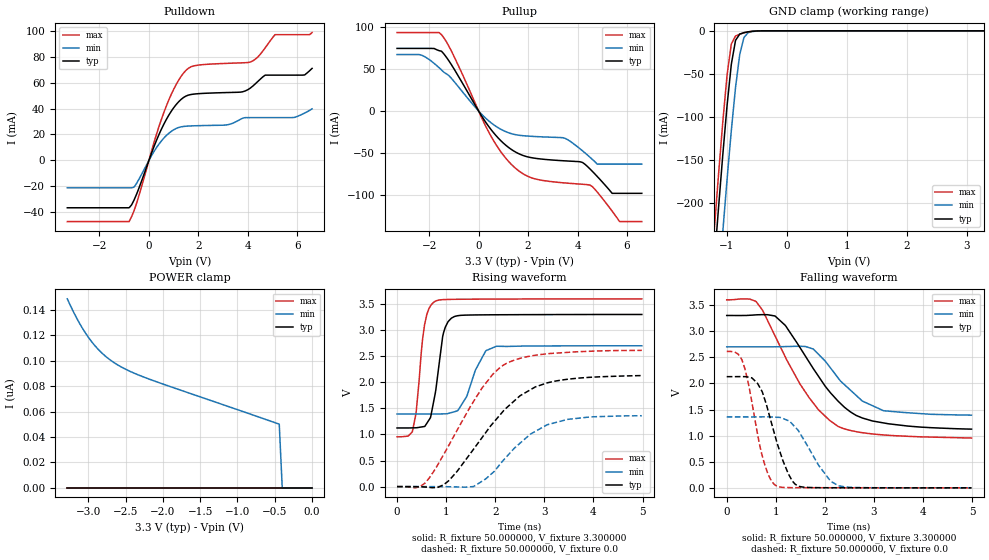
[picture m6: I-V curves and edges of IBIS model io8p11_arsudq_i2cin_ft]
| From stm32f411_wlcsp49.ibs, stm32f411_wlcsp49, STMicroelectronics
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|   Model io8p11_arsudq_i2cin_ft
[Model]  io8p11_arsudq_i2cin_ft
Model_type I/O
Polarity   Non-Inverting
Enable   Active-Low
Vinl =   0.990000V
Vinh =   2.310000V
Vmeas =  1.650000V
Cref =   30.000000pF
Rref =   100.000000M
Vref =   0.0V
C_comp   2.280000pF   2.217100pF   2.355700pF
[Temperature Range]   25.000000   0.125000k   -40.000000
[Pullup Reference]   3.300000V   2.700000V   3.600000V
[Pulldown Reference]   0.0V   0.0V   0.0V
[POWER Clamp Reference]   3.300000V   2.700000V   3.600000V
[GND Clamp Reference]   0.0V   0.0V   0.0V
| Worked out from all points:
|   slope of the pulldown table from 0 to 0.495 V, typ, clamps not added: 20.9 ohm
|   slope of the pullup table from 0 to 0.495 V, typ, clamps not added: 22.6 ohm
|   GND clamp passes 1 mA (typ) near -0.62 V on its own axis
|   rising waveform, R_fixture 50.000000, V_fixture 3.300000: 20-80 % time 197ps typ, 343ps min, 161ps max; typ from 1.12 V to 3.3 V
|   rising waveform, R_fixture 50.000000, V_fixture 0.0: 20-80 % time 1.13ns typ, 914ps min, 1ns max; typ from 0 V to 2.13 V
|   falling waveform, R_fixture 50.000000, V_fixture 3.300000: 20-80 % time 1.01ns typ, 786ps min, 980ps max; typ from 3.3 V to 1.12 V
|   falling waveform, R_fixture 50.000000, V_fixture 0.0: 20-80 % time 415ps typ, 536ps min, 332ps max; typ from 2.13 V to 0 V
[Pulldown]
|Voltage   I(typ)   I(min)   I(max)
-3.3V     -36.46mA   -21.09mA   -47.09mA
-800mV    -36.46mA   -21.09mA   -47.09mA
-600mV    -30.5mA    -20.54mA   -38.69mA
700mV     31.4mA     19.11mA    41.71mA
1.2V      45.15mA    25.37mA    61.75mA
1.6V      50.35mA    26.5mA     71.06mA
3.1V      52.28mA    27.26mA    74.76mA
4.1V      55.7mA     33mA       75.81mA
4.7V      65.72mA    33mA       86.7mA
5.1V      65.72mA    33mA       96.91mA
6.3V      65.88mA    36.51mA    96.91mA
6.6V      70.94mA    39.72mA    98.51mA
[Pullup]
|Voltage   I(typ)   I(min)   I(max)
-3.3V     74.74mA    67.41mA    93.65mA
-2.3V     74.74mA    66.57mA    93.65mA
-1.5V     71.37mA    49mA       91.08mA
500mV     -22.07mA   -14mA      -30.03mA
1.6V      -50.64mA   -28.81mA   -70.96mA
3.5V      -59.53mA   -32.65mA   -85.92mA
4.2V      -61.43mA   -47.49mA   -87.46mA
4.5V      -69.07mA   -55.12mA   -88.38mA
4.8V      -78.23mA   -63.4mA    -96.83mA
5.4V      -98.3mA    -63.4mA    -119.6mA
5.7V      -98.3mA    -63.4mA    -132mA
6.6V      -98.3mA    -63.4mA    -132mA
[GND_clamp]
|Voltage   I(typ)   I(min)   I(max)
-3.3V     -2.317A    -2.396A    -2.289A
-1.2V     -265.5mA   -356.1mA   -227.2mA
-1.13V    -202.6mA   -292.9mA   -164.1mA
-1.06V    -142.2mA   -231.2mA   -104.1mA
-990mV    -85.98mA   -171.6mA   -50.72mA
-920mV    -38.8mA    -115.5mA   -15.28mA
-850mV    -11.08mA   -65.6mA    -6.001mA
-780mV    -3.782mA   -27.42mA   -3.876mA
-710mV    -2.086mA   -7.69mA    -2.381mA
-640mV    -1.147mA   -2.118mA   -1.22mA
-570mV    -523.9uA   -798.4uA   -476.8uA
3.28V     0A         0A         0A
[POWER_clamp]
|Voltage   I(typ)   I(min)   I(max)
-3.28V    0A         148.5nA    0A
-3.2V     0A         138.6nA    0A
-3.12V    0A         129.7nA    0A
-3.04V    0A         122nA      0A
-2.96V    0A         115.3nA    0A
-2.8V     0A         105.1nA    0A
-2.6V     0A         96.44nA    0A
-2.4V     0A         90.52nA    0A
-2.16V    0A         84.97nA    0A
-440mV    0A         50.04nA    0A
-400mV    0A         0A         0A
0V        0A         0A         0A
[Ramp]
| variable   typ   min   max
dV/dt_r  1.26126/1.11621n   0.80562/0.90469n   1.56066/0.99981n
dV/dt_f  1.27692/0.99459n   0.77130/0.76528n   1.56982/0.97122n
R_load = 50.000000
[Rising Waveform]
R_fixture= 50.000000
V_fixture= 3.300000
V_fixture_min= 2.700000
V_fixture_max= 3.600000
|time   V(typ)   V(min)   V(max)
0s        1.124V     1.392V     954.4mV
310.3ps   1.126V     1.392V     1.049V
390.4ps   1.128V     1.392V     1.436V
560.6ps   1.153V     1.392V     3.099V
780.8ps   1.8V       1.391V     3.554V
951ps     2.961V     1.395V     3.585V
1.171ns   3.262V     1.436V     3.59V
1.802ns   3.293V     2.594V     3.594V
2.022ns   3.294V     2.69V      3.595V
4.985ns   3.3V       2.7V       3.599V
[Rising Waveform]
R_fixture= 50.000000
V_fixture= 0.0
V_fixture_min= 0.0
V_fixture_max= 0.0
|time   V(typ)   V(min)   V(max)
0s        345.4uV    196.8uV    641.9uV
470.5ps   -3.051mV   137.9uV    396.5uV
660.7ps   -15.09mV   184.2uV    170.3mV
951ps     36.13mV    -1.055mV   617.8mV
1.562ns   720.9mV    2.76mV     1.636V
1.952ns   1.214V     268.6mV    2.155V
2.202ns   1.487V     543.5mV    2.349V
2.713ns   1.855V     1.003V     2.502V
3.063ns   1.99V      1.187V     2.547V
4.985ns   2.129V     1.359V     2.612V
[Falling Waveform]
R_fixture= 50.000000
V_fixture= 3.300000
V_fixture_min= 2.700000
V_fixture_max= 3.600000
|time   V(typ)   V(min)   V(max)
0s        3.3V       2.7V       3.599V
590.6ps   3.311V     2.7V       3.571V
730.7ps   3.316V     2.7V       3.399V
991ps     3.284V     2.701V     2.895V
1.201ns   3.099V     2.705V     2.49V
1.762ns   2.285V     2.658V     1.625V
2.272ns   1.656V     2.1V       1.174V
2.763ns   1.337V     1.661V     1.056V
3.193ns   1.243V     1.477V     1.013V
4.985ns   1.124V     1.392V     954.4mV
[Falling Waveform]
R_fixture= 50.000000
V_fixture= 0.0
V_fixture_min= 0.0
V_fixture_max= 0.0
|time   V(typ)   V(min)   V(max)
0s        2.129V     1.359V     2.612V
310.3ps   2.129V     1.358V     2.449V
450.5ps   2.118V     1.358V     1.955V
630.6ps   1.995V     1.358V     1.013V
830.8ps   1.516V     1.36V      286.8mV
1.011ns   906.2mV    1.352V     39.04mV
1.391ns   71.92mV    1.165V     3.466mV
1.872ns   3.6mV      431.9mV    2.332mV
2.272ns   2.019mV    42.33mV    1.989mV
4.985ns   345.4uV    196.8uV    641.9uV
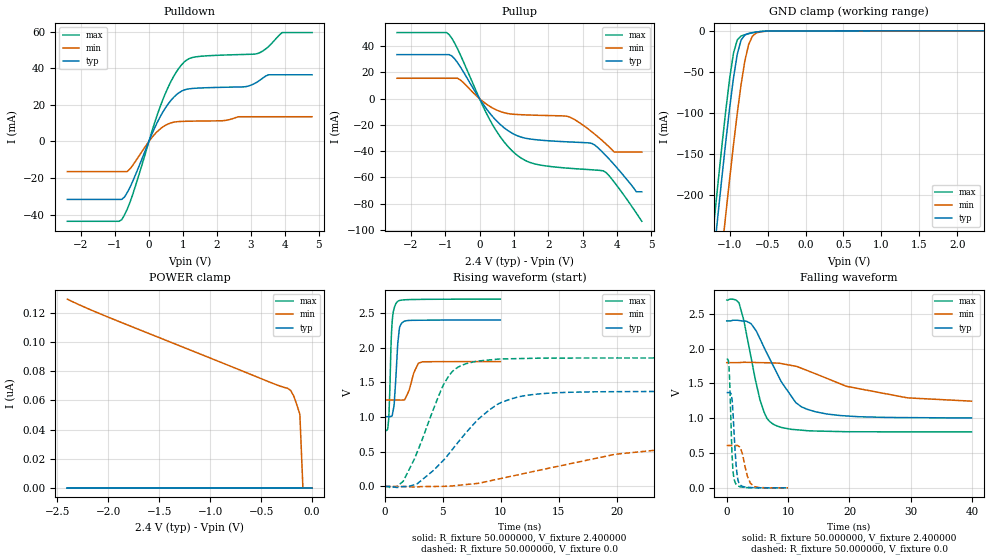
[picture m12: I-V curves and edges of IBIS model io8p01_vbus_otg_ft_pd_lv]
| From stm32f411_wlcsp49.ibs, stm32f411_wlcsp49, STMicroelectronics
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|   Model io8p01_vbus_otg_ft_pd_lv
[Model]  io8p01_vbus_otg_ft_pd_lv
Model_type I/O
Polarity   Non-Inverting
Enable   Active-Low
Vinl =   0.720000V
Vinh =   1.680000V
Vmeas =  1.200000V
Cref =   50.000000pF
Rref =   100.000000M
Vref =   0.0V
C_comp   3.193600pF   3.100000pF   3.332100pF
[Temperature Range]   25.000000   0.125000k   -40.000000
[Pullup Reference]   2.400000V   1.800000V   2.700000V
[Pulldown Reference]   0.0V   0.0V   0.0V
[POWER Clamp Reference]   2.400000V   1.800000V   2.700000V
[GND Clamp Reference]   0.0V   0.0V   0.0V
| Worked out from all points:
|   slope of the pulldown table from 0 to 0.36 V, typ, clamps not added: 25 ohm
|   slope of the pullup table from 0 to 0.36 V, typ, clamps not added: 27.7 ohm
|   GND clamp passes 1 mA (typ) near -0.61 V on its own axis
|   rising waveform, R_fixture 50.000000, V_fixture 2.400000: 20-80 % time 310ps typ, 630ps min, 224ps max; typ from 1 V to 2.4 V
|   rising waveform, R_fixture 50.000000, V_fixture 0.0: 20-80 % time 4.51ns typ, 11ns min, 2.64ns max; typ from 0 V to 1.37 V
|   falling waveform, R_fixture 50.000000, V_fixture 2.400000: 20-80 % time 5.25ns typ, 12.6ns min, 2.75ns max; typ from 2.4 V to 1 V
|   falling waveform, R_fixture 50.000000, V_fixture 0.0: 20-80 % time 574ps typ, 1.04ns min, 434ps max; typ from 1.37 V to 0 V
[Pulldown]
|Voltage   I(typ)   I(min)   I(max)
-2.4V     -31.69mA   -16.5mA    -43.66mA
-800mV    -31.69mA   -16.5mA    -42.82mA
-480mV    -21.96mA   -13.17mA   -29.19mA
80mV      3.63mA     1.966mA    5.014mA
480mV     18.15mA    8.738mA    26.02mA
800mV     25.38mA    10.72mA    37.77mA
1.12V     28.53mA    11.02mA    44.6mA
2.8V      29.84mA    13.49mA    47.53mA
3.2V      32.65mA    13.49mA    48.04mA
3.52V     36.42mA    13.49mA    51.83mA
3.92V     36.42mA    13.49mA    59.49mA
4.8V      36.42mA    13.49mA    59.49mA
[Pullup]
|Voltage   I(typ)   I(min)   I(max)
-2.4V     33.57mA    15.56mA    50.37mA
-960mV    33.57mA    15.56mA    50.37mA
-560mV    24.29mA    14.3mA     33.54mA
320mV     -11.75mA   -6.207mA   -17.08mA
960mV     -26.47mA   -11.82mA   -40.02mA
1.52V     -30.88mA   -12.51mA   -49.05mA
2.56V     -32.88mA   -13.49mA   -52.9mA
3.28V     -34.19mA   -25.52mA   -54.18mA
3.6V      -41.31mA   -32.61mA   -54.99mA
3.92V     -50.33mA   -40.7mA    -63.62mA
4.56V     -70.9mA    -40.7mA    -87.08mA
4.72V     -70.9mA    -40.7mA    -93.4mA
[GND_clamp]
|Voltage   I(typ)   I(min)   I(max)
-2.4V     -1.424A    -1.508A    -1.393A
-1.25V    -311.3mA   -401.9mA   -273.4mA
-1.2V     -265.5mA   -356.1mA   -227.3mA
-1.15V    -220.5mA   -310.9mA   -182mA
-1.1V     -176.4mA   -266.2mA   -138mA
-1.05V    -133.9mA   -222.5mA   -96.06mA
-950mV    -57.51mA   -139mA     -27.36mA
-900mV    -28.55mA   -100.5mA   -11.04mA
-850mV    -11.34mA   -65.68mA   -6.337mA
-750mV    -3.08mA    -16.7mA    -3.439mA
-600mV    -875.9uA   -1.303mA   -865.8uA
2.35V     58.09uA    37.92uA    67.25uA
[POWER_clamp]
|Voltage   I(typ)   I(min)   I(max)
-2.4V     0A         129.4nA    0A
-1.98V    0A         116.5nA    0A
-390mV    0A         71.78nA    0A
-240mV    0A         68.22nA    0A
-210mV    0A         66.81nA    0A
-180mV    0A         62.95nA    0A
-120mV    0A         50.47nA    0A
-90mV     0A         0A         0A
0V        0A         0A         0A
[Ramp]
| variable   typ   min   max
dV/dt_r  0.82152/4.50337n   0.36569/11.19550n   1.11030/2.63503n
dV/dt_f  0.83664/5.24814n   0.32310/13.25187n   1.13800/2.75649n
R_load = 50.000000
[Rising Waveform]
R_fixture= 50.000000
V_fixture= 2.400000
V_fixture_min= 1.800000
V_fixture_max= 2.700000
|time   V(typ)   V(min)   V(max)
0s        1.005V     1.245V     804.2mV
340.3ps   1.005V     1.245V     971mV
560.6ps   1.011V     1.246V     2.142V
640.6ps   1.023V     1.246V     2.377V
800.8ps   1.166V     1.246V     2.564V
1.041ns   1.824V     1.245V     2.654V
1.261ns   2.278V     1.245V     2.679V
1.682ns   2.379V     1.248V     2.689V
2.903ns   2.394V     1.775V     2.695V
9.97ns    2.399V     1.799V     2.699V
[Rising Waveform]
R_fixture= 50.000000
V_fixture= 0.0
V_fixture_min= 0.0
V_fixture_max= 0.0
|time   V(typ)   V(min)   V(max)
0s        177.9uV    73.69uV    454.5uV
1.602ns   -2.589mV   -134.3uV   78.46mV
2.803ns   39.03mV    -5.995mV   498.2mV
5.045ns   375.5mV    1.767mV    1.459V
5.926ns   554mV      9.803mV    1.671V
7.047ns   782.9mV    28.32mV    1.77V
9.69ns    1.181V     103.2mV    1.833V
12.81ns   1.325V     215.7mV    1.846V
26.51ns   1.369V     575.5mV    1.851V
39.88ns   1.369V     608.4mV    1.851V
[Falling Waveform]
R_fixture= 50.000000
V_fixture= 2.400000
V_fixture_min= 1.800000
V_fixture_max= 2.700000
|time   V(typ)   V(min)   V(max)
0s        2.399V     1.799V     2.699V
2.002ns   2.405V     1.8V       2.657V
3.924ns   2.362V     1.803V     1.892V
5.445ns   2.137V     1.799V     1.259V
6.567ns   1.931V     1.798V     998.4mV
7.768ns   1.721V     1.794V     906.3mV
11.29ns   1.222V     1.746V     835.3mV
14.49ns   1.093V     1.638V     816.8mV
29.39ns   1.01V      1.294V     804.6mV
39.88ns   1.005V     1.245V     804.2mV
[Falling Waveform]
R_fixture= 50.000000
V_fixture= 0.0
V_fixture_min= 0.0
V_fixture_max= 0.0
|time   V(typ)   V(min)   V(max)
0s        1.369V     608.4mV    1.851V
380.4ps   1.369V     608.4mV    1.724V
860.9ps   1.272V     608.2mV    502mV
1.061ns   1.018V     607.9mV    211.5mV
1.401ns   487.1mV    608.2mV    71.94mV
1.742ns   156.2mV    609mV      33.4mV
2.342ns   32.68mV    545.9mV    12.79mV
3.343ns   7.353mV    173.2mV    3.719mV
4.464ns   2.401mV    18.12mV    1.328mV
9.97ns    177.9uV    73.69uV    454.5uV
